One B-rep face of a CAD part: STEP entity #1320.
In plain terms, the planar face has unit normal (1, 0, 0).
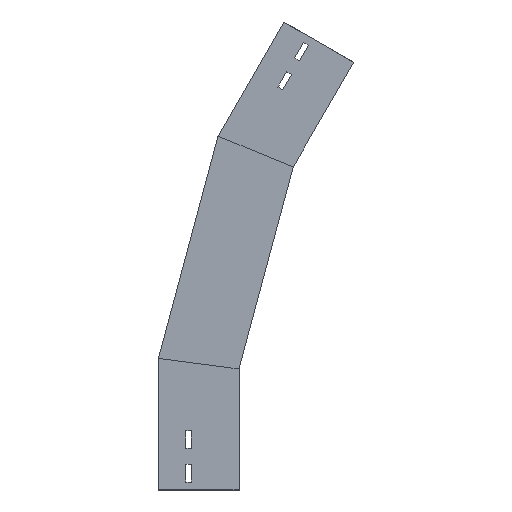
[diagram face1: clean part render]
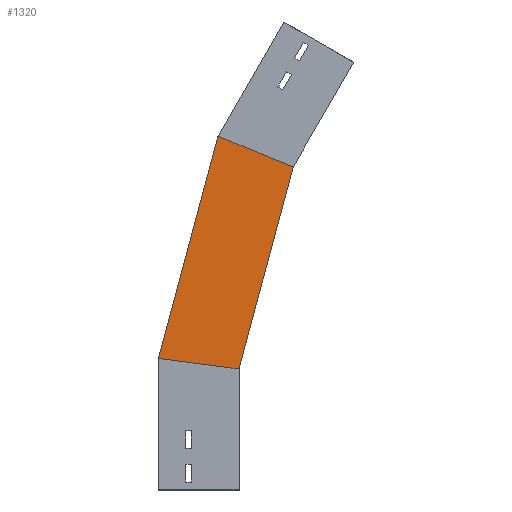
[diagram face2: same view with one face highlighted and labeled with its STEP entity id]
Its self-contained STEP definition (entity closure, numbers rounded to 3 decimals):
#20 = DIRECTION ( 'NONE',  ( 0., -0.991, -0.131 ) ) ;
#103 = ORIENTED_EDGE ( 'NONE', *, *, #470, .F. ) ;
#152 = ORIENTED_EDGE ( 'NONE', *, *, #1430, .F. ) ;
#268 = VERTEX_POINT ( 'NONE', #505 ) ;
#278 = ORIENTED_EDGE ( 'NONE', *, *, #1311, .T. ) ;
#282 = CARTESIAN_POINT ( 'NONE',  ( 0., 26.151, 438.773 ) ) ;
#287 = VERTEX_POINT ( 'NONE', #478 ) ;
#338 = PLANE ( 'NONE',  #1446 ) ;
#342 = CARTESIAN_POINT ( 'NONE',  ( 0., 3.774, 135.915 ) ) ;
#470 = EDGE_CURVE ( 'NONE', #634, #268, #837, .T. ) ;
#474 = DIRECTION ( 'NONE',  ( 1., 0., 0. ) ) ;
#475 = VERTEX_POINT ( 'NONE', #282 ) ;
#478 = CARTESIAN_POINT ( 'NONE',  ( 0., 100., 163.165 ) ) ;
#505 = CARTESIAN_POINT ( 'NONE',  ( 0., -67.034, 400.175 ) ) ;
#508 = DIRECTION ( 'NONE',  ( 0., -0.259, 0.966 ) ) ;
#577 = DIRECTION ( 'NONE',  ( 0., 0., -1. ) ) ;
#619 = EDGE_CURVE ( 'NONE', #287, #475, #1033, .T. ) ;
#634 = VERTEX_POINT ( 'NONE', #1123 ) ;
#658 = EDGE_LOOP ( 'NONE', ( #1286, #278, #103, #152 ) ) ;
#684 = CARTESIAN_POINT ( 'NONE',  ( 0., 100.367, 161.797 ) ) ;
#695 = CARTESIAN_POINT ( 'NONE',  ( 0., -100.025, 386.509 ) ) ;
#837 = LINE ( 'NONE', #1300, #1240 ) ;
#842 = LINE ( 'NONE', #1056, #1121 ) ;
#1033 = LINE ( 'NONE', #684, #1471 ) ;
#1056 = CARTESIAN_POINT ( 'NONE',  ( 0., -19.411, 147.444 ) ) ;
#1121 = VECTOR ( 'NONE', #20, 1000. ) ;
#1123 = CARTESIAN_POINT ( 'NONE',  ( 0., 0., 150. ) ) ;
#1142 = DIRECTION ( 'NONE',  ( 0., -0.259, 0.966 ) ) ;
#1240 = VECTOR ( 'NONE', #508, 1000. ) ;
#1286 = ORIENTED_EDGE ( 'NONE', *, *, #619, .T. ) ;
#1300 = CARTESIAN_POINT ( 'NONE',  ( 0., 3.774, 135.915 ) ) ;
#1311 = EDGE_CURVE ( 'NONE', #475, #268, #1496, .T. ) ;
#1320 = ADVANCED_FACE ( 'NONE', ( #1377 ), #338, .T. ) ;
#1336 = VECTOR ( 'NONE', #1482, 1000. ) ;
#1377 = FACE_OUTER_BOUND ( 'NONE', #658, .T. ) ;
#1430 = EDGE_CURVE ( 'NONE', #287, #634, #842, .T. ) ;
#1446 = AXIS2_PLACEMENT_3D ( 'NONE', #342, #474, #577 ) ;
#1471 = VECTOR ( 'NONE', #1142, 1000. ) ;
#1482 = DIRECTION ( 'NONE',  ( 0., -0.924, -0.383 ) ) ;
#1496 = LINE ( 'NONE', #695, #1336 ) ;
